VERSION 5.7 ;
BUSBITCHARS "[]" ;
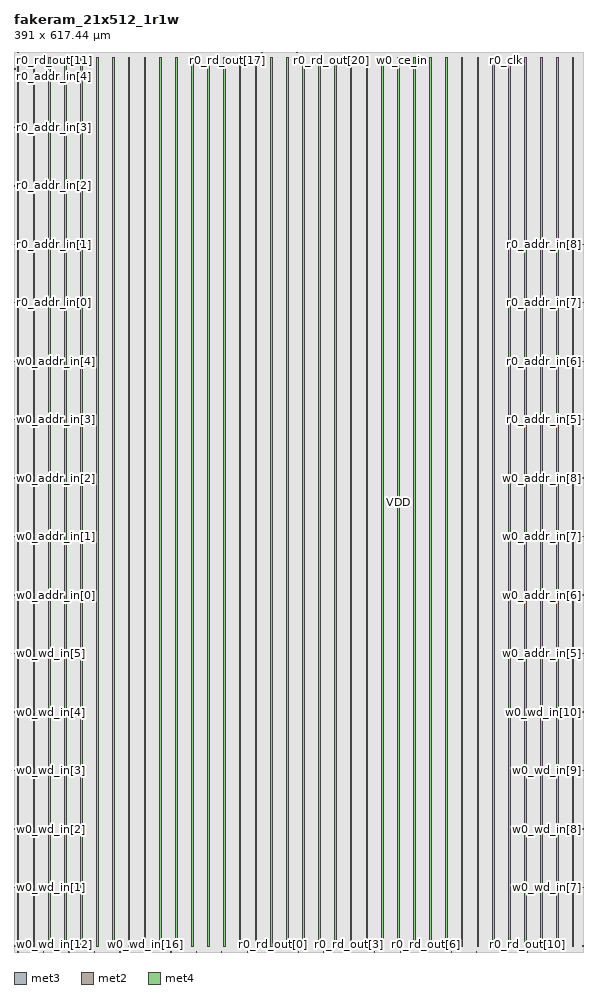
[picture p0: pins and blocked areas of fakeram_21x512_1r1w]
MACRO fakeram_21x512_1r1w
  FOREIGN fakeram_21x512_1r1w 0 0 ;
  SYMMETRY X Y R90 ;
  SIZE 391.000 BY 617.440 ;
  CLASS BLOCK ;
  PIN w0_wd_in[0]
    DIRECTION INPUT ;
    USE SIGNAL ;
    SHAPE ABUTMENT ;
    PORT
      LAYER met3 ;
      RECT 0.000 3.930 0.900 4.230 ;
    END
  END w0_wd_in[0]
  PIN w0_wd_in[1]
    DIRECTION INPUT ;
    USE SIGNAL ;
    SHAPE ABUTMENT ;
    PORT
      LAYER met3 ;
      RECT 0.000 44.050 0.900 44.350 ;
    END
  END w0_wd_in[1]
  PIN w0_wd_in[2]
    DIRECTION INPUT ;
    USE SIGNAL ;
    SHAPE ABUTMENT ;
    PORT
      LAYER met3 ;
      RECT 0.000 84.170 0.900 84.470 ;
    END
  END w0_wd_in[2]
  PIN w0_wd_in[3]
    DIRECTION INPUT ;
    USE SIGNAL ;
    SHAPE ABUTMENT ;
    PORT
      LAYER met3 ;
      RECT 0.000 124.290 0.900 124.590 ;
    END
  END w0_wd_in[3]
  PIN w0_wd_in[4]
    DIRECTION INPUT ;
    USE SIGNAL ;
    SHAPE ABUTMENT ;
    PORT
      LAYER met3 ;
      RECT 0.000 164.410 0.900 164.710 ;
    END
  END w0_wd_in[4]
  PIN w0_wd_in[5]
    DIRECTION INPUT ;
    USE SIGNAL ;
    SHAPE ABUTMENT ;
    PORT
      LAYER met3 ;
      RECT 0.000 204.530 0.900 204.830 ;
    END
  END w0_wd_in[5]
  PIN w0_wd_in[6]
    DIRECTION INPUT ;
    USE SIGNAL ;
    SHAPE ABUTMENT ;
    PORT
      LAYER met3 ;
      RECT 390.100 3.930 391.000 4.230 ;
    END
  END w0_wd_in[6]
  PIN w0_wd_in[7]
    DIRECTION INPUT ;
    USE SIGNAL ;
    SHAPE ABUTMENT ;
    PORT
      LAYER met3 ;
      RECT 390.100 44.050 391.000 44.350 ;
    END
  END w0_wd_in[7]
  PIN w0_wd_in[8]
    DIRECTION INPUT ;
    USE SIGNAL ;
    SHAPE ABUTMENT ;
    PORT
      LAYER met3 ;
      RECT 390.100 84.170 391.000 84.470 ;
    END
  END w0_wd_in[8]
  PIN w0_wd_in[9]
    DIRECTION INPUT ;
    USE SIGNAL ;
    SHAPE ABUTMENT ;
    PORT
      LAYER met3 ;
      RECT 390.100 124.290 391.000 124.590 ;
    END
  END w0_wd_in[9]
  PIN w0_wd_in[10]
    DIRECTION INPUT ;
    USE SIGNAL ;
    SHAPE ABUTMENT ;
    PORT
      LAYER met3 ;
      RECT 390.100 164.410 391.000 164.710 ;
    END
  END w0_wd_in[10]
  PIN w0_wd_in[11]
    DIRECTION OUTPUT ;
    USE SIGNAL ;
    SHAPE ABUTMENT ;
    PORT
      LAYER met2 ;
      RECT 2.690 0.000 2.830 0.420 ;
    END
  END w0_wd_in[11]
  PIN w0_wd_in[12]
    DIRECTION OUTPUT ;
    USE SIGNAL ;
    SHAPE ABUTMENT ;
    PORT
      LAYER met2 ;
      RECT 20.170 0.000 20.310 0.420 ;
    END
  END w0_wd_in[12]
  PIN w0_wd_in[13]
    DIRECTION OUTPUT ;
    USE SIGNAL ;
    SHAPE ABUTMENT ;
    PORT
      LAYER met2 ;
      RECT 37.650 0.000 37.790 0.420 ;
    END
  END w0_wd_in[13]
  PIN w0_wd_in[14]
    DIRECTION OUTPUT ;
    USE SIGNAL ;
    SHAPE ABUTMENT ;
    PORT
      LAYER met2 ;
      RECT 55.130 0.000 55.270 0.420 ;
    END
  END w0_wd_in[14]
  PIN w0_wd_in[15]
    DIRECTION OUTPUT ;
    USE SIGNAL ;
    SHAPE ABUTMENT ;
    PORT
      LAYER met2 ;
      RECT 72.610 0.000 72.750 0.420 ;
    END
  END w0_wd_in[15]
  PIN w0_wd_in[16]
    DIRECTION OUTPUT ;
    USE SIGNAL ;
    SHAPE ABUTMENT ;
    PORT
      LAYER met2 ;
      RECT 90.090 0.000 90.230 0.420 ;
    END
  END w0_wd_in[16]
  PIN w0_wd_in[17]
    DIRECTION OUTPUT ;
    USE SIGNAL ;
    SHAPE ABUTMENT ;
    PORT
      LAYER met2 ;
      RECT 107.570 0.000 107.710 0.420 ;
    END
  END w0_wd_in[17]
  PIN w0_wd_in[18]
    DIRECTION OUTPUT ;
    USE SIGNAL ;
    SHAPE ABUTMENT ;
    PORT
      LAYER met2 ;
      RECT 125.050 0.000 125.190 0.420 ;
    END
  END w0_wd_in[18]
  PIN w0_wd_in[19]
    DIRECTION OUTPUT ;
    USE SIGNAL ;
    SHAPE ABUTMENT ;
    PORT
      LAYER met2 ;
      RECT 142.530 0.000 142.670 0.420 ;
    END
  END w0_wd_in[19]
  PIN w0_wd_in[20]
    DIRECTION OUTPUT ;
    USE SIGNAL ;
    SHAPE ABUTMENT ;
    PORT
      LAYER met2 ;
      RECT 160.010 0.000 160.150 0.420 ;
    END
  END w0_wd_in[20]
  PIN r0_rd_out[0]
    DIRECTION OUTPUT ;
    USE SIGNAL ;
    SHAPE ABUTMENT ;
    PORT
      LAYER met2 ;
      RECT 177.490 0.000 177.630 0.420 ;
    END
  END r0_rd_out[0]
  PIN r0_rd_out[1]
    DIRECTION OUTPUT ;
    USE SIGNAL ;
    SHAPE ABUTMENT ;
    PORT
      LAYER met2 ;
      RECT 194.970 0.000 195.110 0.420 ;
    END
  END r0_rd_out[1]
  PIN r0_rd_out[2]
    DIRECTION OUTPUT ;
    USE SIGNAL ;
    SHAPE ABUTMENT ;
    PORT
      LAYER met2 ;
      RECT 212.450 0.000 212.590 0.420 ;
    END
  END r0_rd_out[2]
  PIN r0_rd_out[3]
    DIRECTION OUTPUT ;
    USE SIGNAL ;
    SHAPE ABUTMENT ;
    PORT
      LAYER met2 ;
      RECT 229.930 0.000 230.070 0.420 ;
    END
  END r0_rd_out[3]
  PIN r0_rd_out[4]
    DIRECTION OUTPUT ;
    USE SIGNAL ;
    SHAPE ABUTMENT ;
    PORT
      LAYER met2 ;
      RECT 247.410 0.000 247.550 0.420 ;
    END
  END r0_rd_out[4]
  PIN r0_rd_out[5]
    DIRECTION OUTPUT ;
    USE SIGNAL ;
    SHAPE ABUTMENT ;
    PORT
      LAYER met2 ;
      RECT 264.890 0.000 265.030 0.420 ;
    END
  END r0_rd_out[5]
  PIN r0_rd_out[6]
    DIRECTION OUTPUT ;
    USE SIGNAL ;
    SHAPE ABUTMENT ;
    PORT
      LAYER met2 ;
      RECT 282.370 0.000 282.510 0.420 ;
    END
  END r0_rd_out[6]
  PIN r0_rd_out[7]
    DIRECTION OUTPUT ;
    USE SIGNAL ;
    SHAPE ABUTMENT ;
    PORT
      LAYER met2 ;
      RECT 299.850 0.000 299.990 0.420 ;
    END
  END r0_rd_out[7]
  PIN r0_rd_out[8]
    DIRECTION OUTPUT ;
    USE SIGNAL ;
    SHAPE ABUTMENT ;
    PORT
      LAYER met2 ;
      RECT 317.330 0.000 317.470 0.420 ;
    END
  END r0_rd_out[8]
  PIN r0_rd_out[9]
    DIRECTION OUTPUT ;
    USE SIGNAL ;
    SHAPE ABUTMENT ;
    PORT
      LAYER met2 ;
      RECT 334.810 0.000 334.950 0.420 ;
    END
  END r0_rd_out[9]
  PIN r0_rd_out[10]
    DIRECTION OUTPUT ;
    USE SIGNAL ;
    SHAPE ABUTMENT ;
    PORT
      LAYER met2 ;
      RECT 352.290 0.000 352.430 0.420 ;
    END
  END r0_rd_out[10]
  PIN r0_rd_out[11]
    DIRECTION OUTPUT ;
    USE SIGNAL ;
    SHAPE ABUTMENT ;
    PORT
      LAYER met2 ;
      RECT 2.690 617.020 2.830 617.440 ;
    END
  END r0_rd_out[11]
  PIN r0_rd_out[12]
    DIRECTION OUTPUT ;
    USE SIGNAL ;
    SHAPE ABUTMENT ;
    PORT
      LAYER met2 ;
      RECT 26.610 617.020 26.750 617.440 ;
    END
  END r0_rd_out[12]
  PIN r0_rd_out[13]
    DIRECTION OUTPUT ;
    USE SIGNAL ;
    SHAPE ABUTMENT ;
    PORT
      LAYER met2 ;
      RECT 50.530 617.020 50.670 617.440 ;
    END
  END r0_rd_out[13]
  PIN r0_rd_out[14]
    DIRECTION OUTPUT ;
    USE SIGNAL ;
    SHAPE ABUTMENT ;
    PORT
      LAYER met2 ;
      RECT 74.450 617.020 74.590 617.440 ;
    END
  END r0_rd_out[14]
  PIN r0_rd_out[15]
    DIRECTION OUTPUT ;
    USE SIGNAL ;
    SHAPE ABUTMENT ;
    PORT
      LAYER met2 ;
      RECT 98.370 617.020 98.510 617.440 ;
    END
  END r0_rd_out[15]
  PIN r0_rd_out[16]
    DIRECTION OUTPUT ;
    USE SIGNAL ;
    SHAPE ABUTMENT ;
    PORT
      LAYER met2 ;
      RECT 122.290 617.020 122.430 617.440 ;
    END
  END r0_rd_out[16]
  PIN r0_rd_out[17]
    DIRECTION OUTPUT ;
    USE SIGNAL ;
    SHAPE ABUTMENT ;
    PORT
      LAYER met2 ;
      RECT 146.210 617.020 146.350 617.440 ;
    END
  END r0_rd_out[17]
  PIN r0_rd_out[18]
    DIRECTION OUTPUT ;
    USE SIGNAL ;
    SHAPE ABUTMENT ;
    PORT
      LAYER met2 ;
      RECT 170.130 617.020 170.270 617.440 ;
    END
  END r0_rd_out[18]
  PIN r0_rd_out[19]
    DIRECTION OUTPUT ;
    USE SIGNAL ;
    SHAPE ABUTMENT ;
    PORT
      LAYER met2 ;
      RECT 194.050 617.020 194.190 617.440 ;
    END
  END r0_rd_out[19]
  PIN r0_rd_out[20]
    DIRECTION OUTPUT ;
    USE SIGNAL ;
    SHAPE ABUTMENT ;
    PORT
      LAYER met2 ;
      RECT 217.970 617.020 218.110 617.440 ;
    END
  END r0_rd_out[20]
  PIN w0_addr_in[0]
    DIRECTION INPUT ;
    USE SIGNAL ;
    SHAPE ABUTMENT ;
    PORT
      LAYER met3 ;
      RECT 0.000 244.650 0.900 244.950 ;
    END
  END w0_addr_in[0]
  PIN w0_addr_in[1]
    DIRECTION INPUT ;
    USE SIGNAL ;
    SHAPE ABUTMENT ;
    PORT
      LAYER met3 ;
      RECT 0.000 284.770 0.900 285.070 ;
    END
  END w0_addr_in[1]
  PIN w0_addr_in[2]
    DIRECTION INPUT ;
    USE SIGNAL ;
    SHAPE ABUTMENT ;
    PORT
      LAYER met3 ;
      RECT 0.000 324.890 0.900 325.190 ;
    END
  END w0_addr_in[2]
  PIN w0_addr_in[3]
    DIRECTION INPUT ;
    USE SIGNAL ;
    SHAPE ABUTMENT ;
    PORT
      LAYER met3 ;
      RECT 0.000 365.010 0.900 365.310 ;
    END
  END w0_addr_in[3]
  PIN w0_addr_in[4]
    DIRECTION INPUT ;
    USE SIGNAL ;
    SHAPE ABUTMENT ;
    PORT
      LAYER met3 ;
      RECT 0.000 405.130 0.900 405.430 ;
    END
  END w0_addr_in[4]
  PIN w0_addr_in[5]
    DIRECTION INPUT ;
    USE SIGNAL ;
    SHAPE ABUTMENT ;
    PORT
      LAYER met3 ;
      RECT 390.100 204.530 391.000 204.830 ;
    END
  END w0_addr_in[5]
  PIN w0_addr_in[6]
    DIRECTION INPUT ;
    USE SIGNAL ;
    SHAPE ABUTMENT ;
    PORT
      LAYER met3 ;
      RECT 390.100 244.650 391.000 244.950 ;
    END
  END w0_addr_in[6]
  PIN w0_addr_in[7]
    DIRECTION INPUT ;
    USE SIGNAL ;
    SHAPE ABUTMENT ;
    PORT
      LAYER met3 ;
      RECT 390.100 284.770 391.000 285.070 ;
    END
  END w0_addr_in[7]
  PIN w0_addr_in[8]
    DIRECTION INPUT ;
    USE SIGNAL ;
    SHAPE ABUTMENT ;
    PORT
      LAYER met3 ;
      RECT 390.100 324.890 391.000 325.190 ;
    END
  END w0_addr_in[8]
  PIN r0_addr_in[0]
    DIRECTION INPUT ;
    USE SIGNAL ;
    SHAPE ABUTMENT ;
    PORT
      LAYER met3 ;
      RECT 0.000 445.250 0.900 445.550 ;
    END
  END r0_addr_in[0]
  PIN r0_addr_in[1]
    DIRECTION INPUT ;
    USE SIGNAL ;
    SHAPE ABUTMENT ;
    PORT
      LAYER met3 ;
      RECT 0.000 485.370 0.900 485.670 ;
    END
  END r0_addr_in[1]
  PIN r0_addr_in[2]
    DIRECTION INPUT ;
    USE SIGNAL ;
    SHAPE ABUTMENT ;
    PORT
      LAYER met3 ;
      RECT 0.000 525.490 0.900 525.790 ;
    END
  END r0_addr_in[2]
  PIN r0_addr_in[3]
    DIRECTION INPUT ;
    USE SIGNAL ;
    SHAPE ABUTMENT ;
    PORT
      LAYER met3 ;
      RECT 0.000 565.610 0.900 565.910 ;
    END
  END r0_addr_in[3]
  PIN r0_addr_in[4]
    DIRECTION INPUT ;
    USE SIGNAL ;
    SHAPE ABUTMENT ;
    PORT
      LAYER met3 ;
      RECT 0.000 605.730 0.900 606.030 ;
    END
  END r0_addr_in[4]
  PIN r0_addr_in[5]
    DIRECTION INPUT ;
    USE SIGNAL ;
    SHAPE ABUTMENT ;
    PORT
      LAYER met3 ;
      RECT 390.100 365.010 391.000 365.310 ;
    END
  END r0_addr_in[5]
  PIN r0_addr_in[6]
    DIRECTION INPUT ;
    USE SIGNAL ;
    SHAPE ABUTMENT ;
    PORT
      LAYER met3 ;
      RECT 390.100 405.130 391.000 405.430 ;
    END
  END r0_addr_in[6]
  PIN r0_addr_in[7]
    DIRECTION INPUT ;
    USE SIGNAL ;
    SHAPE ABUTMENT ;
    PORT
      LAYER met3 ;
      RECT 390.100 445.250 391.000 445.550 ;
    END
  END r0_addr_in[7]
  PIN r0_addr_in[8]
    DIRECTION INPUT ;
    USE SIGNAL ;
    SHAPE ABUTMENT ;
    PORT
      LAYER met3 ;
      RECT 390.100 485.370 391.000 485.670 ;
    END
  END r0_addr_in[8]
  PIN w0_we_in
    DIRECTION INPUT ;
    USE SIGNAL ;
    SHAPE ABUTMENT ;
    PORT
      LAYER met2 ;
      RECT 241.890 617.020 242.030 617.440 ;
    END
  END w0_we_in
  PIN w0_ce_in
    DIRECTION INPUT ;
    USE SIGNAL ;
    SHAPE ABUTMENT ;
    PORT
      LAYER met2 ;
      RECT 265.810 617.020 265.950 617.440 ;
    END
  END w0_ce_in
  PIN w0_clk
    DIRECTION INPUT ;
    USE SIGNAL ;
    SHAPE ABUTMENT ;
    PORT
      LAYER met2 ;
      RECT 289.730 617.020 289.870 617.440 ;
    END
  END w0_clk
  PIN r0_ce_in
    DIRECTION INPUT ;
    USE SIGNAL ;
    SHAPE ABUTMENT ;
    PORT
      LAYER met2 ;
      RECT 313.650 617.020 313.790 617.440 ;
    END
  END r0_ce_in
  PIN r0_clk
    DIRECTION INPUT ;
    USE SIGNAL ;
    SHAPE ABUTMENT ;
    PORT
      LAYER met2 ;
      RECT 337.570 617.020 337.710 617.440 ;
    END
  END r0_clk
  PIN VSS
    DIRECTION INOUT ;
    USE GROUND ;
    PORT
      LAYER met4 ;
      RECT 2.160 4.080 3.360 613.360 ;
      RECT 13.040 4.080 14.240 613.360 ;
      RECT 23.920 4.080 25.120 613.360 ;
      RECT 34.800 4.080 36.000 613.360 ;
      RECT 45.680 4.080 46.880 613.360 ;
      RECT 56.560 4.080 57.760 613.360 ;
      RECT 67.440 4.080 68.640 613.360 ;
      RECT 78.320 4.080 79.520 613.360 ;
      RECT 89.200 4.080 90.400 613.360 ;
      RECT 100.080 4.080 101.280 613.360 ;
      RECT 110.960 4.080 112.160 613.360 ;
      RECT 121.840 4.080 123.040 613.360 ;
      RECT 132.720 4.080 133.920 613.360 ;
      RECT 143.600 4.080 144.800 613.360 ;
      RECT 154.480 4.080 155.680 613.360 ;
      RECT 165.360 4.080 166.560 613.360 ;
      RECT 176.240 4.080 177.440 613.360 ;
      RECT 187.120 4.080 188.320 613.360 ;
      RECT 198.000 4.080 199.200 613.360 ;
      RECT 208.880 4.080 210.080 613.360 ;
      RECT 219.760 4.080 220.960 613.360 ;
      RECT 230.640 4.080 231.840 613.360 ;
      RECT 241.520 4.080 242.720 613.360 ;
      RECT 252.400 4.080 253.600 613.360 ;
      RECT 263.280 4.080 264.480 613.360 ;
      RECT 274.160 4.080 275.360 613.360 ;
      RECT 285.040 4.080 286.240 613.360 ;
      RECT 295.920 4.080 297.120 613.360 ;
      RECT 306.800 4.080 308.000 613.360 ;
      RECT 317.680 4.080 318.880 613.360 ;
      RECT 328.560 4.080 329.760 613.360 ;
      RECT 339.440 4.080 340.640 613.360 ;
      RECT 350.320 4.080 351.520 613.360 ;
      RECT 361.200 4.080 362.400 613.360 ;
      RECT 372.080 4.080 373.280 613.360 ;
      RECT 382.960 4.080 384.160 613.360 ;
    END
  END VSS
  PIN VDD
    DIRECTION INOUT ;
    USE POWER ;
    PORT
      LAYER met4 ;
      RECT 2.160 4.080 3.360 613.360 ;
      RECT 13.040 4.080 14.240 613.360 ;
      RECT 23.920 4.080 25.120 613.360 ;
      RECT 34.800 4.080 36.000 613.360 ;
      RECT 45.680 4.080 46.880 613.360 ;
      RECT 56.560 4.080 57.760 613.360 ;
      RECT 67.440 4.080 68.640 613.360 ;
      RECT 78.320 4.080 79.520 613.360 ;
      RECT 89.200 4.080 90.400 613.360 ;
      RECT 100.080 4.080 101.280 613.360 ;
      RECT 110.960 4.080 112.160 613.360 ;
      RECT 121.840 4.080 123.040 613.360 ;
      RECT 132.720 4.080 133.920 613.360 ;
      RECT 143.600 4.080 144.800 613.360 ;
      RECT 154.480 4.080 155.680 613.360 ;
      RECT 165.360 4.080 166.560 613.360 ;
      RECT 176.240 4.080 177.440 613.360 ;
      RECT 187.120 4.080 188.320 613.360 ;
      RECT 198.000 4.080 199.200 613.360 ;
      RECT 208.880 4.080 210.080 613.360 ;
      RECT 219.760 4.080 220.960 613.360 ;
      RECT 230.640 4.080 231.840 613.360 ;
      RECT 241.520 4.080 242.720 613.360 ;
      RECT 252.400 4.080 253.600 613.360 ;
      RECT 263.280 4.080 264.480 613.360 ;
      RECT 274.160 4.080 275.360 613.360 ;
      RECT 285.040 4.080 286.240 613.360 ;
      RECT 295.920 4.080 297.120 613.360 ;
      RECT 306.800 4.080 308.000 613.360 ;
      RECT 317.680 4.080 318.880 613.360 ;
      RECT 328.560 4.080 329.760 613.360 ;
      RECT 339.440 4.080 340.640 613.360 ;
      RECT 350.320 4.080 351.520 613.360 ;
      RECT 361.200 4.080 362.400 613.360 ;
      RECT 372.080 4.080 373.280 613.360 ;
      RECT 382.960 4.080 384.160 613.360 ;
    END
  END VDD
  OBS
    LAYER met1 ;
    RECT 0 0 391.000 617.440 ;
    LAYER met2 ;
    RECT 0 0 391.000 617.440 ;
    LAYER met3 ;
    RECT 0 0 391.000 617.440 ;
    LAYER met4 ;
    RECT 0 0 391.000 617.440 ;
  END
END fakeram_21x512_1r1w

END LIBRARY
